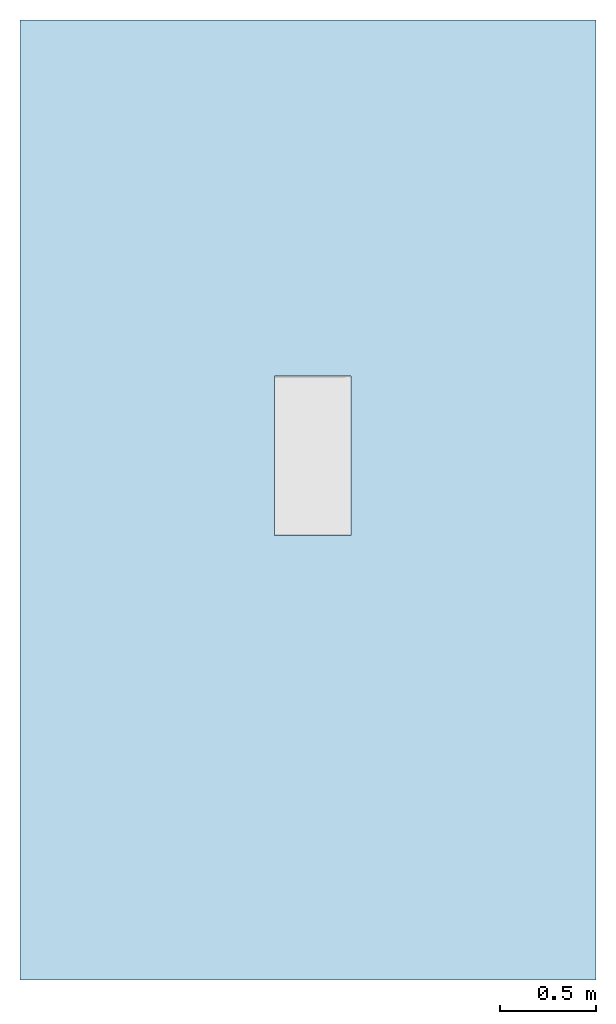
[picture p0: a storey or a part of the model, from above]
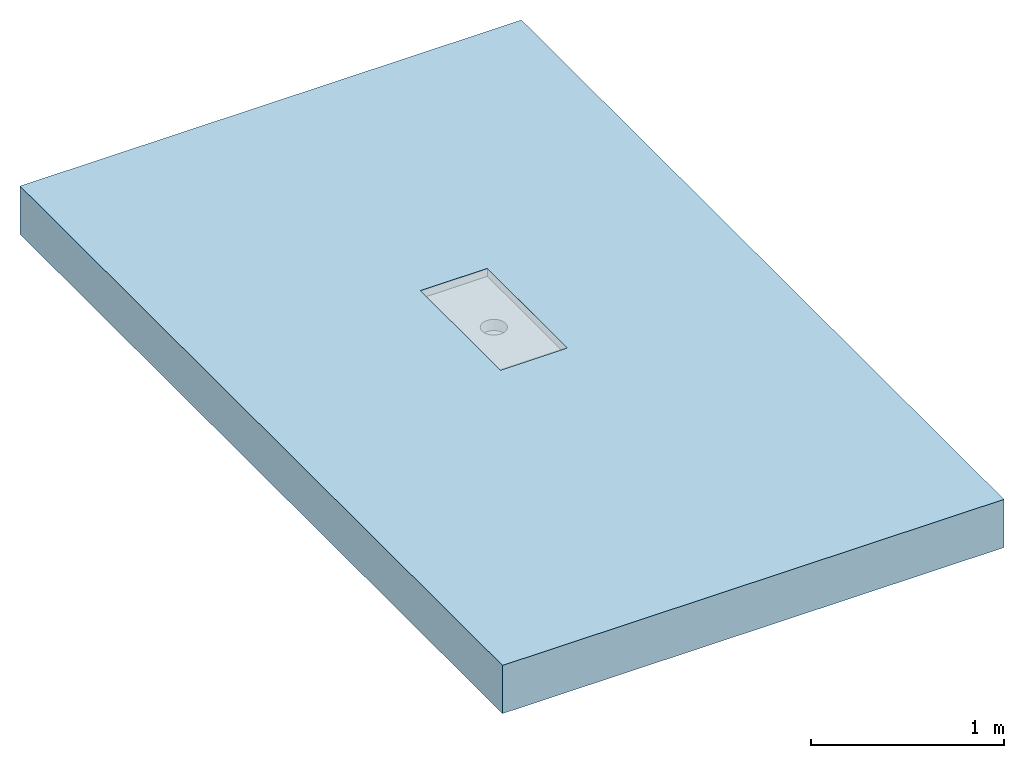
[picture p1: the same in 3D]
Properties of the parts of a building model (IFC2X3)

# File
Description: ViewDefinition [CoordinationView]
File name: Project Number
Time: 2016-11-22T11:12:26
Written by: The EXPRESS Data Manager Version 5.01.0100.02.64mod : 6 Jun 2012
Made in: 20130308_1515(x64) - Exporter 2014.0.2013.0308 - Default UI
Comment: STEP Physical File produced by: The EXPRESS Data Manager Version 5.01.0100.02.64mod : 6 Jun 2012 * Module: EDMstepFileFactory/EDMstandAlone * Creation date: Tue Nov 22 11:12:26 2016 * Host: IN-BLR-PC-0012 * Database: C:\Users\pakumar\AppData\Local\Temp\{31D3F684-CDA3-43C0-B090-EF764BB159AD}\ifc * Database version: 5507 * Database creation date: Tue Nov 22 11:12:25 2016 * Schema: IFC2X3 * Model: DataRepository.ifc * Model creation date: Tue Nov 22 11:12:25 2016 * Header model: DataRepository.ifc_HeaderModel * Header model creation date: Tue Nov 22 11:12:25 2016 * EDMuser: sdai-user * EDMgroup: sdai-group * License ID and type: 5605 : Permanent license. Expiry date: * EDMstepFileFactory options: 020000

# IfcProject, Project Number
LongName: Project Name; Phase: Project Status

# IfcSite, Default
RefLatitude: 42, 21, 30, 344238; RefLongitude: -71, -3, -35, -194702; RefElevation: 0 mm

# IfcBuilding
Pset_BuildingCommon - NumberOfStoreys: 1
Other - Project Issue Date: Issue Date; Client Name: Owner; Project Number: Project Number; Project Status: Project Status; Project Name: Project Name; Project Address: Enter address here

# IfcBuildingStorey, Level 1
LongName: Level 1; Elevation: 0 mm
Constraints - Elevation Base: Project Base Point; Elevation: 0 mm
Graphics - Symbol at End 2 Default: yes; Color: 0; Line Weight: 1; Symbol: Level Head - Circle: Level Head - Circle; Symbol at End 1 Default: no; Line Pattern: Grid Line 1/2"
Identity Data - Name: Level 1; Structural: no; Building Story: yes
Dimensions - Computation Height: 0 mm

# IfcFlowTerminal: 416644 - Hygienic Standard Channel - with Gully 157 - 800mm LG - 400mm Wide, ACO Tray Channel - Hygienic - Standard - 400mm Wide:416644 - Hygienic Standard Channel - with Gully 157 - 800mm LG - 400mm Wide:688386
In: Level 1
Material: Stainless Steel AISI 304, Stainless Steel AISI 304 - Grating
Other - Number mesh: 17; Flow: 0.0988811 m3/s; Hygienic Standard Channel - 600mm LG - 400mm Wide: no; Spigot Outlets Channels: yes; Hygienic Standard Channel - 400mm LG - 400mm Wide: no; Hygienic Standard Channel - 800mm LG - 400mm Wide: yes; Invert Depth Detail: 51.5 mm
Construction - 416890 - 368 x 598mm - Mesh Grating - L15 - Stainless Steel 1.4301: no; 416868 - 368 x 398mm - Mesh Grating - L15 - Stainless Steel 1.4301: yes; 416826 - 368 x 598mm - Ladder Grating - M125 - Stainless Steel 1.4301: no; 416822 - 368 x 598mm - Ladder Grating - R50 - Stainless Steel 1.4301: no; 416870 - 368 x 598mm - Mesh Grating - L15 - Stainless Steel 1.4301: no; 416820 - 368 x 398mm - Ladder Grating - R50 - Stainless Steel 1.4301: no; 416888 - 368 x 398mm - Mesh Grating - L15 - Stainless Steel 1.4301: no; 416824 - 368 x 398mm - Ladder Grating - M125 - Stainless Steel 1.4301: no; Grating: yes; Detail - Outlet 142mm: yes; Detail - Outlet 200: no
Phasing - Phase Created: New Construction
Mechanical - System Classification: Sanitary
Identity Data - Mark: 60; Address: ACO Business Centre, Caxton Road, Bedford, MK41 0LF; Website: www.acobd.com; Watermarked With: BIM Manager Premium Suite.; E-mail Technical: abdtechnical@aco.co.uk; Watermarked By: www.acobd.com; E-mail Sales: abdcommercial@aco.co.uk; Watermark2: This file is water marked and users are prohibited to reproduce, adapt, distribute this information.; Cost: 0; Manufacturer: ACO Building Drainage; Fax: +44 (0)1462 851490; Watermark1: This file is the property of ACO Technologies PLC.; Telephone: +44 (0)1462 816666
Constraints - Level: Level: Level 1
Pset_ManufacturerTypeInformation - Manufacturer: ACO Building Drainage
Model Properties - Grating Product Code 416820: Load Class R 50 (EN 1253) - Ladder Grate - Stainless steel 1.4301 (EN 10088) - 368 x 398 - 6.9kg; Grating Product Code 416888: Load Class L 15 (EN 1253) - Mesh Grate - Stainless steel 1.4301 (EN 10088) - 368 x 398 - 4.1kg; Grating Product Code 416822: N/A; Grating Product Code 416824: Load Class M 125 (EN 1253) - Ladder Grate - Stainless steel 1.4301 (EN 10088) - 368 x 398 - 9.4kg; Grating Product Code 416870: N/A; Grating Product Code 416868: Load Class L 15 (EN 1253) - Mesh Grate - Stainless steel 1.4301 (EN 10088) - 368 x 398 - 4.0kg; Grating Product Code 416890: N/A; Grating Product Code 416826: N/A
Dimensions - x: -815 mm; Grating Height: 21 mm; Inside Outlet Rad: 66 mm; End Connection Plate Start: -770 mm; End Plate: 800 mm; Grating Length: 499 mm; Outlet: 142 mm; Invert Depth: 50 mm; Number of gratings: 2; Endplate Position: 800 mm; Depth: 29 mm; Floor Cut Void Height: 62.8 mm; Grating Void Cut Length: 500 mm; Length Channel: -770 mm; End Connection Plate End: -800 mm; Spigot Distance: 400 mm; Outside Outlet Rad: 71 mm
General - Foul air trap Recyclable: Fully recyclable; Product Code: 416644; Foul air trap seal Material: NBR; Load Class: A15 - C250 (EN 1253); Channel Material: Stainless steel 1.4301 (EN 10088); Product Standard: EN 1253 / EN 1672 / EN ISO 14159; Foul air trap Recycled material content: 0%; Channel Colour: passivated stainless steel surface ( matt grey); Product Description: ACO Hygiene First Standard Kitchen Tray Channel 400 x 830 / 142 Dia Outlet & Foul Air Trap; Channel Recycled material content: 20 - 30 %; Channel Recyclable: Fully recyclable; Outlet Diameter (mm): 142; Price: POA - contact ACO; Installation guidelines: http://issuu.com/acobuildingdrainage/docs/aco_hygiene_first_catalogue/17?e=0; Maintenance guidelines: http://issuu.com/acobuildingdrainage/docs/aco_hygiene_first_catalogue/17?e=0; Product Type: Standard Kitchen Tray Channel; Channel Dimension: 400 x 830; Weight (Kg): 6.3; Foul air trap seal Colour: Black; Product Range: ACO Hygiene First

# IfcOpeningElement: Recess
In: Level 1
Dimensions - Area: 161.459 ft2; Perimeter: 16000 mm; Volume: 160.833 ft3; Thickness: 304.8 mm
Constraints - Height Offset From Level: 0 mm; Room Bounding: yes; Level: Level: Level 1; Related to Mass: no
Structural - Enable Analytical Model: no; Structural: no
Phasing - Phase Created: New Construction
Graphics - Coarse Scale Fill Color: 0
Analytical Properties - Absorptance: 0.7; Roughness: 3
Construction - Default Thickness: 304.8 mm; Function: Interior
Identity Data - Assembly Description: Floor Construction; Assembly Code: B1010

# IfcSlab: Floor:Generic - 12", Floor:Generic - 12":184145
In: Level 1
PredefinedType: FLOOR; Material: Default Floor 304.8 mm
Dimensions - Area: 161.459 ft2; Perimeter: 16000 mm; Volume: 160.833 ft3; Thickness: 304.8 mm
Constraints - Height Offset From Level: 0 mm; Room Bounding: yes; Level: Level: Level 1; Related to Mass: no
Structural - Enable Analytical Model: no; Structural: no
Phasing - Phase Created: New Construction
Pset_SlabCommon - Reference: Generic - 12"; IsExternal: no; LoadBearing: yes
Graphics - Coarse Scale Fill Color: 0
Analytical Properties - Absorptance: 0.7; Roughness: 3
Construction - Default Thickness: 304.8 mm; Function: Interior
Identity Data - Assembly Description: Floor Construction; Assembly Code: B1010
